VERSION 5.8 ;
DIVIDERCHAR "/" ;
BUSBITCHARS "[]" ;

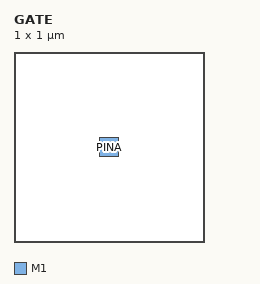
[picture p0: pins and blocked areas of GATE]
MACRO GATE
  CLASS CORE ;
  ORIGIN 0.000 0.000 ;
  SIZE 1.000 BY 1.000 ;
  SYMMETRY X Y ;
  PIN PINA
    DIRECTION INPUT ;
    USE SIGNAL ;
    ANTENNAMODEL OXIDE1 ;
    ANTENNAGATEAREA 1 ;
    PORT
      LAYER M1 ;
        RECT 0.450 0.450 0.550 0.550 ;
    END
  END PINA
END GATE

END LIBRARY
